VERSION 5.7 ;
  NOWIREEXTENSIONATPIN ON ;
  DIVIDERCHAR "/" ;
  BUSBITCHARS "[]" ;
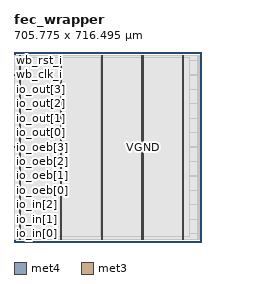
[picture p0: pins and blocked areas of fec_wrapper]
MACRO fec_wrapper
  CLASS BLOCK ;
  FOREIGN fec_wrapper ;
  ORIGIN 0.000 0.000 ;
  SIZE 705.775 BY 716.495 ;
  PIN VGND
    DIRECTION INOUT ;
    USE GROUND ;
    PORT
      LAYER met4 ;
        RECT 24.340 10.640 25.940 704.720 ;
    END
    PORT
      LAYER met4 ;
        RECT 177.940 10.640 179.540 704.720 ;
    END
    PORT
      LAYER met4 ;
        RECT 331.540 10.640 333.140 704.720 ;
    END
    PORT
      LAYER met4 ;
        RECT 485.140 10.640 486.740 704.720 ;
    END
    PORT
      LAYER met4 ;
        RECT 638.740 10.640 640.340 704.720 ;
    END
  END VGND
  PIN VPWR
    DIRECTION INOUT ;
    USE POWER ;
    PORT
      LAYER met4 ;
        RECT 21.040 10.640 22.640 704.720 ;
    END
    PORT
      LAYER met4 ;
        RECT 174.640 10.640 176.240 704.720 ;
    END
    PORT
      LAYER met4 ;
        RECT 328.240 10.640 329.840 704.720 ;
    END
    PORT
      LAYER met4 ;
        RECT 481.840 10.640 483.440 704.720 ;
    END
    PORT
      LAYER met4 ;
        RECT 635.440 10.640 637.040 704.720 ;
    END
  END VPWR
  PIN io_in[0]
    DIRECTION INPUT ;
    USE SIGNAL ;
    ANTENNAGATEAREA 0.213000 ;
    ANTENNADIFFAREA 2.673000 ;
    PORT
      LAYER met3 ;
        RECT 0.000 31.320 0.600 31.920 ;
    END
  END io_in[0]
  PIN io_in[1]
    DIRECTION INPUT ;
    USE SIGNAL ;
    ANTENNAGATEAREA 0.213000 ;
    ANTENNADIFFAREA 2.673000 ;
    PORT
      LAYER met3 ;
        RECT 0.000 85.720 0.600 86.320 ;
    END
  END io_in[1]
  PIN io_in[2]
    DIRECTION INPUT ;
    USE SIGNAL ;
    ANTENNAGATEAREA 0.213000 ;
    ANTENNADIFFAREA 2.673000 ;
    PORT
      LAYER met3 ;
        RECT 0.000 140.120 0.600 140.720 ;
    END
  END io_in[2]
  PIN io_oeb[0]
    DIRECTION OUTPUT ;
    USE SIGNAL ;
    PORT
      LAYER met3 ;
        RECT 0.000 194.520 0.600 195.120 ;
    END
  END io_oeb[0]
  PIN io_oeb[1]
    DIRECTION OUTPUT ;
    USE SIGNAL ;
    PORT
      LAYER met3 ;
        RECT 0.000 248.920 0.600 249.520 ;
    END
  END io_oeb[1]
  PIN io_oeb[2]
    DIRECTION OUTPUT ;
    USE SIGNAL ;
    PORT
      LAYER met3 ;
        RECT 0.000 303.320 0.600 303.920 ;
    END
  END io_oeb[2]
  PIN io_oeb[3]
    DIRECTION OUTPUT ;
    USE SIGNAL ;
    PORT
      LAYER met3 ;
        RECT 0.000 357.720 0.600 358.320 ;
    END
  END io_oeb[3]
  PIN io_out[0]
    DIRECTION OUTPUT ;
    USE SIGNAL ;
    ANTENNADIFFAREA 2.673000 ;
    PORT
      LAYER met3 ;
        RECT 0.000 412.120 0.600 412.720 ;
    END
  END io_out[0]
  PIN io_out[1]
    DIRECTION OUTPUT ;
    USE SIGNAL ;
    ANTENNADIFFAREA 2.673000 ;
    PORT
      LAYER met3 ;
        RECT 0.000 466.520 0.600 467.120 ;
    END
  END io_out[1]
  PIN io_out[2]
    DIRECTION OUTPUT ;
    USE SIGNAL ;
    ANTENNADIFFAREA 2.673000 ;
    PORT
      LAYER met3 ;
        RECT 0.000 520.920 0.600 521.520 ;
    END
  END io_out[2]
  PIN io_out[3]
    DIRECTION OUTPUT ;
    USE SIGNAL ;
    ANTENNADIFFAREA 2.673000 ;
    PORT
      LAYER met3 ;
        RECT 0.000 575.320 0.600 575.920 ;
    END
  END io_out[3]
  PIN wb_clk_i
    DIRECTION INPUT ;
    USE SIGNAL ;
    ANTENNAGATEAREA 1.286700 ;
    ANTENNADIFFAREA 0.434700 ;
    PORT
      LAYER met3 ;
        RECT 0.000 629.720 0.600 630.320 ;
    END
  END wb_clk_i
  PIN wb_rst_i
    DIRECTION INPUT ;
    USE SIGNAL ;
    ANTENNAGATEAREA 0.159000 ;
    ANTENNADIFFAREA 0.434700 ;
    PORT
      LAYER met3 ;
        RECT 0.000 684.120 0.600 684.720 ;
    END
  END wb_rst_i
  OBS
      LAYER nwell ;
        RECT 5.330 10.795 700.310 704.670 ;
      LAYER li1 ;
        RECT 5.520 10.795 700.120 704.565 ;
      LAYER met1 ;
        RECT 1.450 10.640 700.120 704.720 ;
      LAYER met2 ;
        RECT 0.550 10.695 695.880 704.665 ;
      LAYER met3 ;
        RECT 0.525 685.120 691.775 704.645 ;
        RECT 1.000 683.720 691.775 685.120 ;
        RECT 0.525 630.720 691.775 683.720 ;
        RECT 1.000 629.320 691.775 630.720 ;
        RECT 0.525 576.320 691.775 629.320 ;
        RECT 1.000 574.920 691.775 576.320 ;
        RECT 0.525 521.920 691.775 574.920 ;
        RECT 1.000 520.520 691.775 521.920 ;
        RECT 0.525 467.520 691.775 520.520 ;
        RECT 1.000 466.120 691.775 467.520 ;
        RECT 0.525 413.120 691.775 466.120 ;
        RECT 1.000 411.720 691.775 413.120 ;
        RECT 0.525 358.720 691.775 411.720 ;
        RECT 1.000 357.320 691.775 358.720 ;
        RECT 0.525 304.320 691.775 357.320 ;
        RECT 1.000 302.920 691.775 304.320 ;
        RECT 0.525 249.920 691.775 302.920 ;
        RECT 1.000 248.520 691.775 249.920 ;
        RECT 0.525 195.520 691.775 248.520 ;
        RECT 1.000 194.120 691.775 195.520 ;
        RECT 0.525 141.120 691.775 194.120 ;
        RECT 1.000 139.720 691.775 141.120 ;
        RECT 0.525 86.720 691.775 139.720 ;
        RECT 1.000 85.320 691.775 86.720 ;
        RECT 0.525 32.320 691.775 85.320 ;
        RECT 1.000 30.920 691.775 32.320 ;
        RECT 0.525 10.715 691.775 30.920 ;
      LAYER met4 ;
        RECT 23.295 20.575 23.940 697.505 ;
        RECT 26.340 20.575 174.240 697.505 ;
        RECT 176.640 20.575 177.540 697.505 ;
        RECT 179.940 20.575 327.840 697.505 ;
        RECT 330.240 20.575 331.140 697.505 ;
        RECT 333.540 20.575 481.440 697.505 ;
        RECT 483.840 20.575 484.740 697.505 ;
        RECT 487.140 20.575 635.040 697.505 ;
        RECT 637.440 20.575 638.340 697.505 ;
        RECT 640.740 20.575 662.105 697.505 ;
  END
END fec_wrapper
END LIBRARY

